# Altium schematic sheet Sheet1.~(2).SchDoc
size A

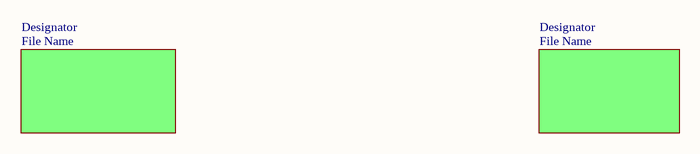
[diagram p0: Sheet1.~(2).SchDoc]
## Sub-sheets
Designator = File Name: no entries
Designator = File Name: no entries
